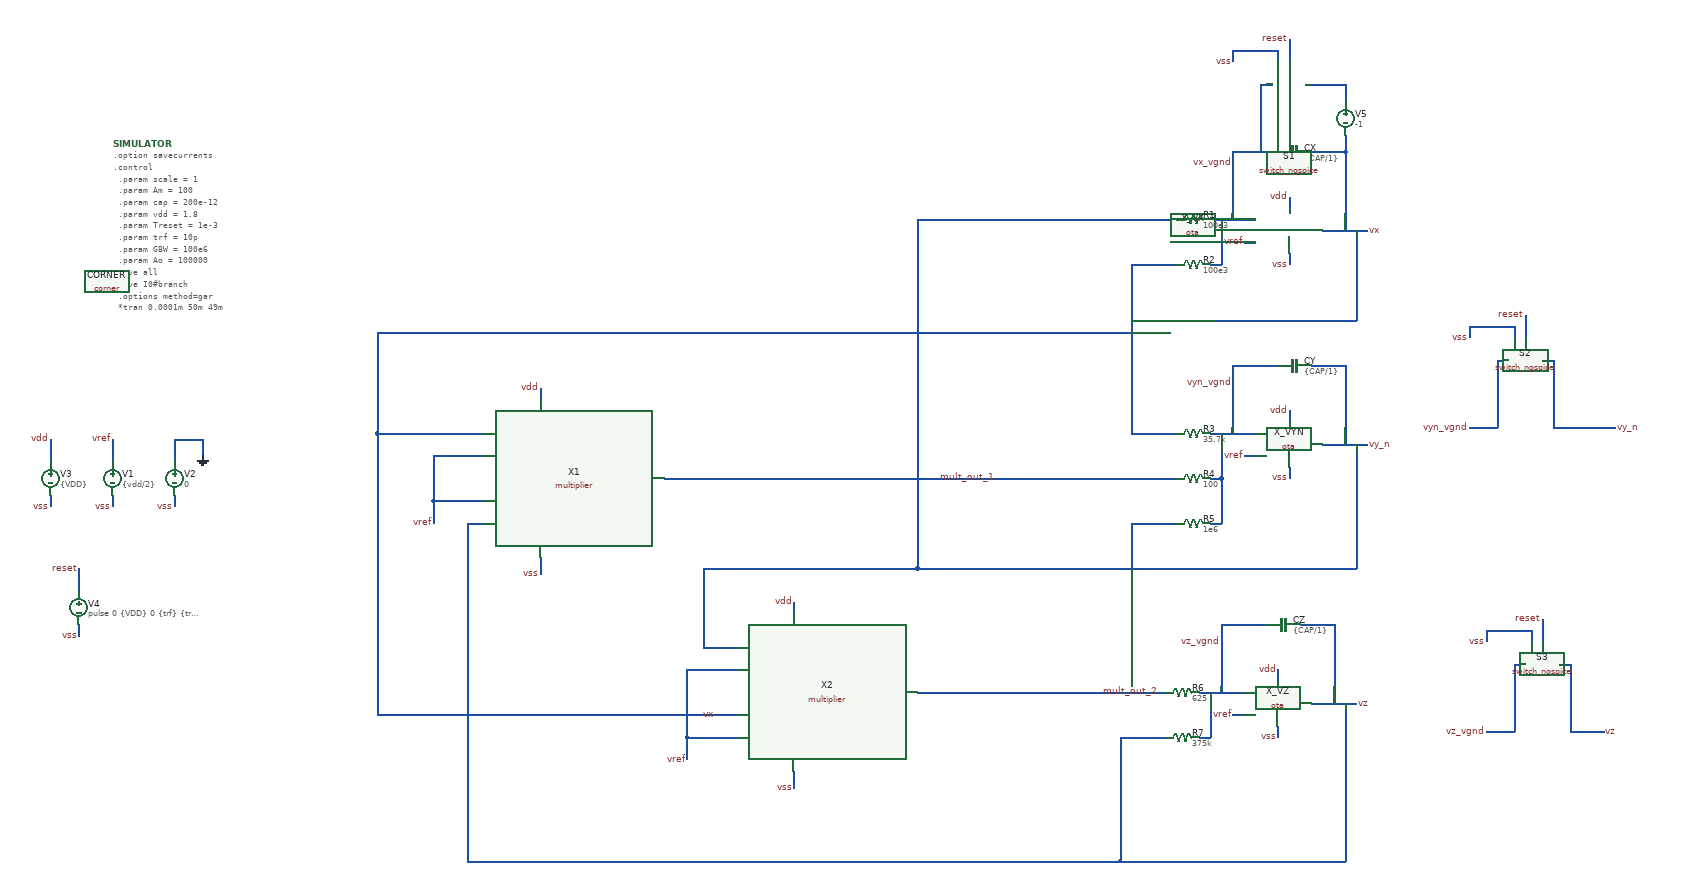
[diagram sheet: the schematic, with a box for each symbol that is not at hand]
v {xschem version=3.4.6 file_version=1.2}
G {}
K {}
V {}
S {}
E {}
N 400 -420 420 -420 {lab=vref}
N 340 -460 420 -460 {lab=vx_vgnd}
N 380 -540 380 -460 {lab=vx_vgnd}
N 380 -580 380 -540 {lab=vx_vgnd}
N 380 -580 460 -580 {lab=vx_vgnd}
N 540 -440 620 -440 {lab=vx}
N 580 -580 580 -440 {lab=vx}
N 520 -580 580 -580 {lab=vx}
N 200 -460 280 -460 {lab=vy_n}
N 200 -380 280 -380 {lab=vx}
N 340 -380 360 -380 {lab=vx_vgnd}
N 360 -460 360 -380 {lab=vx_vgnd}
N 480 -400 480 -380 {lab=vss}
N 400 -40 420 -40 {lab=vref}
N 340 -80 420 -80 {lab=vyn_vgnd}
N 380 -160 380 -80 {lab=vyn_vgnd}
N 380 -200 380 -160 {lab=vyn_vgnd}
N 380 -200 460 -200 {lab=vyn_vgnd}
N 540 -60 620 -60 {lab=vy_n}
N 580 -200 580 -60 {lab=vy_n}
N 520 -200 580 -200 {lab=vy_n}
N 200 -80 280 -80 {lab=vx}
N 200 0 280 0 {lab=mult_out_1}
N 340 0 360 0 {lab=vyn_vgnd}
N 360 -80 360 0 {lab=vyn_vgnd}
N 480 -20 480 0 {lab=vss}
N 340 80 360 80 {lab=vyn_vgnd}
N 360 -0 360 80 {lab=vyn_vgnd}
N 380 420 400 420 {lab=vref}
N 320 380 400 380 {lab=vz_vgnd}
N 360 300 360 380 {lab=vz_vgnd}
N 360 260 360 300 {lab=vz_vgnd}
N 360 260 440 260 {lab=vz_vgnd}
N 520 400 600 400 {lab=vz}
N 560 260 560 400 {lab=vz}
N 500 260 560 260 {lab=vz}
N 180 380 260 380 {lab=mult_out_2}
N 180 460 260 460 {lab=vz}
N 320 460 340 460 {lab=vz_vgnd}
N 340 380 340 460 {lab=vz_vgnd}
N 460 440 460 460 {lab=vss}
N 200 -380 200 -80 {lab=vx}
N 600 -440 600 -280 {lab=vx}
N 200 -280 600 -280 {lab=vx}
N -180 -460 200 -460 {lab=vy_n}
N -180 -460 -180 80 {lab=vy_n}
N 600 -60 600 160 {lab=vy_n}
N -180 160 600 160 {lab=vy_n}
N 200 80 280 80 {lab=vy_n}
N 200 80 200 160 {lab=vy_n}
N 580 400 580 680 {lab=vz}
N 180 460 180 680 {lab=vz}
N -1610 30 -1610 50 {lab=vss}
N -1610 -70 -1610 -30 {lab=vref}
N -1500 30 -1500 50 {lab=vss}
N -1500 -70 -1500 -30 {lab=GND}
N -1450 -70 -1450 -40 {lab=GND}
N -1500 -70 -1450 -70 {lab=GND}
N -1720 30 -1720 50 {lab=vss}
N -1720 -70 -1720 -30 {lab=vdd}
N -280 0 200 -0 {lab=mult_out_1}
N 430 -700 450 -700 {lab=vx_vgnd}
N 430 -700 430 -580 {lab=vx_vgnd}
N 510 -700 530 -700 {lab=#net1}
N 460 -760 460 -740 {lab=vss}
N 380 -760 460 -760 {lab=vss}
N 380 -760 380 -740 {lab=vss}
N 480 -780 480 -740 {lab=reset}
N 850 -210 870 -210 {lab=vyn_vgnd}
N 850 -210 850 -90 {lab=vyn_vgnd}
N 930 -210 950 -210 {lab=vy_n}
N 950 -210 950 -90 {lab=vy_n}
N 880 -270 880 -250 {lab=vss}
N 800 -270 880 -270 {lab=vss}
N 800 -270 800 -250 {lab=vss}
N 900 -290 900 -250 {lab=reset}
N 800 -90 850 -90 {lab=vyn_vgnd}
N 950 -90 1010 -90 {lab=vy_n}
N 880 330 900 330 {lab=vz_vgnd}
N 880 330 880 450 {lab=vz_vgnd}
N 960 330 980 330 {lab=vz}
N 980 330 980 450 {lab=vz}
N 910 270 910 290 {lab=vss}
N 830 270 910 270 {lab=vss}
N 830 270 830 290 {lab=vss}
N 930 250 930 290 {lab=reset}
N 830 450 880 450 {lab=vz_vgnd}
N 980 450 1040 450 {lab=vz}
N -1670 260 -1670 280 {lab=vss}
N -1670 160 -1670 200 {lab=reset}
N 1010 -90 1060 -90 {lab=vy_n}
N 580 -700 580 -670 {lab=#net1}
N 530 -700 580 -700 {lab=#net1}
N 580 -610 580 -580 {lab=vx}
N 180 680 580 680 {lab=vz}
N -180 80 -180 160 {lab=vy_n}
N -630 0 -280 0 {lab=mult_out_1}
N -180 380 180 380 {lab=mult_out_2}
N 480 -120 480 -100 {lab=vdd}
N 480 -500 480 -480 {lab=vdd}
N 460 340 460 360 {lab=vdd}
N -1010 -80 -960 -80 {lab=vx}
N -850 -160 -850 -140 {lab=vdd}
N -850 150 -850 170 {lab=vss}
N -850 140 -850 150 {lab=vss}
N -990 -40 -950 -40 {lab=vref}
N -1040 -40 -1040 40 {lab=vref}
N -990 40 -950 40 {lab=vref}
N -960 -80 -950 -80 {lab=vx}
N -560 300 -510 300 {lab=vy_n}
N -560 460 -510 460 {lab=vref}
N -400 220 -400 240 {lab=vdd}
N -400 530 -400 550 {lab=vss}
N -400 520 -400 530 {lab=vss}
N -540 340 -500 340 {lab=vref}
N -540 420 -500 420 {lab=vx}
N -510 460 -500 460 {lab=vref}
N -510 300 -500 300 {lab=vy_n}
N -590 340 -540 340 {lab=vref}
N -590 340 -590 460 {lab=vref}
N -590 460 -560 460 {lab=vref}
N -1010 -260 200 -260 {lab=vx}
N -1140 -260 -1140 -80 {lab=vx}
N -560 160 -180 160 {lab=vy_n}
N -560 160 -560 300 {lab=vy_n}
N -1140 -260 -1010 -260 {lab=vx}
N -1140 -80 -1010 -80 {lab=vx}
N -1140 -80 -1140 420 {lab=vx}
N -1140 420 -540 420 {lab=vx}
N -590 460 -590 500 {lab=vref}
N -1040 40 -1040 80 {lab=vref}
N -980 680 180 680 {lab=vz}
N -980 80 -980 680 {lab=vz}
N -980 80 -950 80 {lab=vz}
N -1040 -40 -990 -40 {lab=vref}
N -1040 40 -990 40 {lab=vref}
C {behavioral/ota.sym} 480 -440 0 0 {name=X_VX Ao=\{Ao\} VDD=\{VDD\} VSAT=0.25 GBW=\{GBW\} Rout_ol=100}
C {devices/lab_wire.sym} 400 -420 0 0 {name=p1 sig_type=std_logic lab=vref}
C {devices/res.sym} 310 -460 3 0 {name=R1
value=100e3
footprint=1206
device=resistor
m=1}
C {devices/capa.sym} 490 -580 1 0 {name=CX
m=1
value=\{CAP/1\}
footprint=1206
device="ceramic capacitor"}
C {devices/lab_wire.sym} 620 -440 0 1 {name=p2 sig_type=std_logic lab=vx}
C {devices/res.sym} 310 -380 3 0 {name=R2
value=100e3
footprint=1206
device=resistor
m=1}
C {devices/lab_wire.sym} 480 -380 3 0 {name=p3 sig_type=std_logic lab=vss}
C {behavioral/ota.sym} 480 -60 0 0 {name=X_VYN Ao=\{Ao\} VDD=\{VDD\} VSAT=0.25 GBW=\{GBW\} Rout_ol=100}
C {devices/lab_wire.sym} 400 -40 0 0 {name=p4 sig_type=std_logic lab=vref}
C {devices/res.sym} 310 -80 3 0 {name=R3
value=35.7k
footprint=1206
device=resistor
m=1}
C {devices/capa.sym} 490 -200 1 0 {name=CY
m=1
value=\{CAP/1\}
footprint=1206
device="ceramic capacitor"}
C {devices/lab_wire.sym} 620 -60 0 1 {name=p5 sig_type=std_logic lab=vy_n}
C {devices/res.sym} 310 0 3 0 {name=R4
value=100
footprint=1206
device=resistor
m=1}
C {devices/lab_wire.sym} 480 0 3 0 {name=p6 sig_type=std_logic lab=vss}
C {devices/res.sym} 310 80 3 0 {name=R5
value=1e6
footprint=1206
device=resistor
m=1}
C {behavioral/ota.sym} 460 400 0 0 {name=X_VZ Ao=\{Ao\} VDD=\{VDD\} VSAT=0.25 GBW=\{GBW\} Rout_ol=100}
C {devices/lab_wire.sym} 380 420 0 0 {name=p7 sig_type=std_logic lab=vref}
C {devices/res.sym} 290 380 3 0 {name=R6
value=625
footprint=1206
device=resistor
m=1}
C {devices/capa.sym} 470 260 1 0 {name=CZ
m=1
value=\{CAP/1\}
footprint=1206
device="ceramic capacitor"}
C {devices/lab_wire.sym} 600 400 0 1 {name=p8 sig_type=std_logic lab=vz}
C {devices/res.sym} 290 460 3 0 {name=R7
value=375k
footprint=1206
device=resistor
m=1}
C {devices/lab_wire.sym} 460 460 3 0 {name=p9 sig_type=std_logic lab=vss}
C {devices/vsource.sym} -1610 0 0 0 {name=V1 value=\{vdd/2\} savecurrent=false}
C {devices/lab_wire.sym} -1610 50 3 0 {name=p14 sig_type=std_logic lab=vss}
C {devices/lab_wire.sym} -1610 -70 3 1 {name=p15 sig_type=std_logic lab=vref}
C {devices/vsource.sym} -1500 0 0 0 {name=V2 value=0 savecurrent=false}
C {devices/lab_wire.sym} -1500 50 3 0 {name=p16 sig_type=std_logic lab=vss}
C {devices/gnd.sym} -1450 -40 0 0 {name=l1 lab=GND}
C {devices/vsource.sym} -1720 0 0 0 {name=V3 value=\{VDD\} savecurrent=false}
C {devices/lab_wire.sym} -1720 50 3 0 {name=p17 sig_type=std_logic lab=vss}
C {devices/lab_wire.sym} -1720 -70 3 1 {name=p18 sig_type=std_logic lab=vdd}
C {devices/code.sym} -1607.5 -595 0 0 {name=SIMULATOR only_toplevel=false value=
"
.option savecurrents

.control
  
  .param scale = 1
  .param Am = 100
  .param cap = 200e-12
  .param vdd = 1.8
  .param Treset = 1e-3
  .param trf = 10p
  .param GBW = 100e6
  .param Ao = 100000


  save all
  save I0#branch

  .options method=gar
  *tran 0.0001m 50m 49m
   tran 0.01e-3 20m
 
  plot v(vx) v(vy_n) v(vz)
  plot v(vz) vs v(vx) retraceplot

  write lorenz_behavioral.raw
  *quit 0
.endc

"}
C {sky130_fd_pr/corner.sym} -1620 -350 0 0 {name=CORNER only_toplevel=false corner=tt
}
C {devices/lab_wire.sym} 380 -560 3 0 {name=p19 sig_type=std_logic lab=vx_vgnd}
C {devices/lab_wire.sym} 380 -170 3 0 {name=p20 sig_type=std_logic lab=vyn_vgnd}
C {devices/lab_wire.sym} 360 290 3 0 {name=p21 sig_type=std_logic lab=vz_vgnd}
C {devices/lab_wire.sym} -40 0 0 0 {name=p22 sig_type=std_logic lab=mult_out_1}
C {devices/lab_wire.sym} 250 380 0 0 {name=p23 sig_type=std_logic lab=mult_out_2}
C {devices/lab_wire.sym} 380 -740 3 0 {name=p24 sig_type=std_logic lab=vss}
C {devices/lab_wire.sym} 480 -780 3 1 {name=p25 sig_type=std_logic lab=reset}
C {devices/lab_wire.sym} 800 -250 3 0 {name=p26 sig_type=std_logic lab=vss}
C {devices/lab_wire.sym} 900 -290 3 1 {name=p27 sig_type=std_logic lab=reset}
C {devices/lab_wire.sym} 800 -90 0 0 {name=p30 sig_type=std_logic lab=vyn_vgnd}
C {devices/lab_wire.sym} 1060 -90 0 1 {name=p31 sig_type=std_logic lab=vy_n}
C {devices/lab_wire.sym} 830 290 3 0 {name=p28 sig_type=std_logic lab=vss}
C {devices/lab_wire.sym} 930 250 3 1 {name=p29 sig_type=std_logic lab=reset}
C {devices/lab_wire.sym} 830 450 0 0 {name=p32 sig_type=std_logic lab=vz_vgnd}
C {devices/lab_wire.sym} 1040 450 0 1 {name=p33 sig_type=std_logic lab=vz}
C {devices/lab_wire.sym} -1670 280 3 0 {name=p34 sig_type=std_logic lab=vss}
C {devices/lab_wire.sym} -1670 160 3 1 {name=p35 sig_type=std_logic lab=reset}
C {devices/vsource.sym} -1670 230 0 0 {name=V4 value="pulse 0 \{VDD\} 0 \{trf\} \{trf\} \{Treset\} 1e9" savecurrent=false}
C {devices/switch_ngspice.sym} 480 -700 1 0 {name=S1 model=SW1
device_model=".MODEL SW1 SW( VT=\{VDD/2\} VH=0.01 RON=0.01 ROFF=1e99 )"}
C {devices/switch_ngspice.sym} 900 -210 1 0 {name=S2 model=SW1
device_model=".MODEL SW1 SW( VT=\{VDD/2\} VH=0.01 RON=0.01 ROFF=1e99 )"}
C {devices/switch_ngspice.sym} 930 330 1 0 {name=S3 model=SW1
device_model=".MODEL SW1 SW( VT=\{VDD/2\} VH=0.01 RON=0.01 ROFF=1e99 )"}
C {devices/vsource.sym} 580 -640 0 0 {name=V5 value=-1 savecurrent=false}
C {devices/lab_wire.sym} 480 -120 3 1 {name=p12 sig_type=std_logic lab=vdd}
C {devices/lab_wire.sym} 480 -500 3 1 {name=p13 sig_type=std_logic lab=vdd}
C {devices/lab_wire.sym} 460 340 3 1 {name=p36 sig_type=std_logic lab=vdd}
C {behavioral/multiplier.sym} -850 -60 0 0 {name=X1 VDD=1.8 VSAT=0.25 BW=10e6 GAIN=100}
C {devices/lab_wire.sym} -850 -160 3 1 {name=p39 sig_type=std_logic lab=vdd}
C {devices/lab_wire.sym} -850 170 3 0 {name=p40 sig_type=std_logic lab=vss}
C {behavioral/multiplier.sym} -400 320 0 0 {name=X2 VDD=1.8 VSAT=0.25 BW=10e6 GAIN=100}
C {devices/lab_wire.sym} -540 420 0 0 {name=p43 sig_type=std_logic lab=vx}
C {devices/lab_wire.sym} -400 220 3 1 {name=p44 sig_type=std_logic lab=vdd}
C {devices/lab_wire.sym} -400 550 3 0 {name=p45 sig_type=std_logic lab=vss}
C {devices/lab_wire.sym} -590 500 3 0 {name=p46 sig_type=std_logic lab=vref}
C {devices/lab_wire.sym} -1040 80 3 0 {name=p10 sig_type=std_logic lab=vref}
